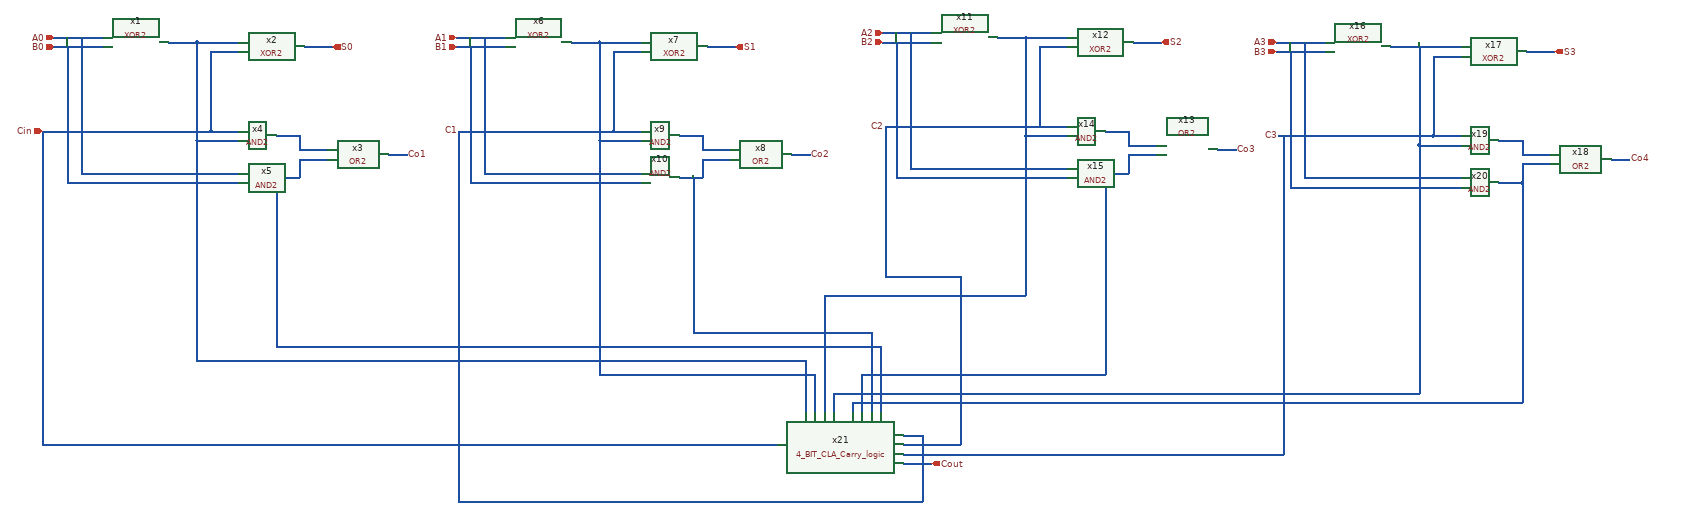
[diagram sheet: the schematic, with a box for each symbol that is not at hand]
v {xschem version=3.4.5 file_version=1.2
}
G {}
K {}
V {}
S {}
E {}
N 1850 -1470 1850 -1440 {
lab=#net1}
N 1850 -1440 1910 -1440 {
lab=#net1}
N 1850 -1420 1850 -1380 {
lab=#net2}
N 1850 -1420 1910 -1420 {
lab=#net2}
N 1660 -1650 1720 -1650 {
lab=Cin}
N 1660 -1650 1660 -1490 {
lab=Cin}
N 1660 -1490 1660 -1480 {
lab=Cin}
N 1660 -1480 1720 -1480 {
lab=Cin}
N 1630 -1460 1720 -1460 {
lab=#net3}
N 1630 -1670 1630 -1460 {
lab=#net3}
N 1630 -1670 1720 -1670 {
lab=#net3}
N 1570 -1670 1630 -1670 {
lab=#net3}
N 1800 -1470 1850 -1470 {
lab=#net1}
N 1800 -1380 1850 -1380 {
lab=#net2}
N 2040 -1430 2080 -1430 {
lab=Co1}
N 1860 -1660 1920 -1660 {
lab=S0}
N 1325 -1680 1430 -1680 {
lab=A0}
N 1325 -1660 1430 -1660 {
lab=B0}
N 1385 -1390 1720 -1390 {
lab=A0}
N 1385 -1680 1385 -1390 {
lab=A0}
N 1355 -1370 1720 -1370 {
lab=B0}
N 1355 -1660 1355 -1370 {
lab=B0}
N 1330 -1480 1660 -1480 {
lab=Cin}
N 2710 -1470 2710 -1440 {
lab=#net4}
N 2710 -1440 2770 -1440 {
lab=#net4}
N 2710 -1420 2710 -1380 {
lab=#net5}
N 2710 -1420 2770 -1420 {
lab=#net5}
N 2520 -1650 2580 -1650 {
lab=C1}
N 2520 -1650 2520 -1490 {
lab=C1}
N 2520 -1490 2520 -1480 {
lab=C1}
N 2520 -1480 2580 -1480 {
lab=C1}
N 2490 -1460 2580 -1460 {
lab=#net6}
N 2490 -1670 2490 -1460 {
lab=#net6}
N 2490 -1670 2580 -1670 {
lab=#net6}
N 2430 -1670 2490 -1670 {
lab=#net6}
N 2660 -1470 2710 -1470 {
lab=#net4}
N 2660 -1380 2710 -1380 {
lab=#net5}
N 2900 -1430 2940 -1430 {
lab=Co2}
N 2720 -1660 2780 -1660 {
lab=S1}
N 2185 -1680 2290 -1680 {
lab=A1}
N 2185 -1660 2290 -1660 {
lab=B1}
N 2245 -1390 2580 -1390 {
lab=A1}
N 2245 -1680 2245 -1390 {
lab=A1}
N 2215 -1370 2580 -1370 {
lab=B1}
N 2215 -1660 2215 -1370 {
lab=B1}
N 2190 -1480 2520 -1480 {
lab=C1}
N 3620 -1480 3620 -1450 {
lab=#net7}
N 3620 -1450 3680 -1450 {
lab=#net7}
N 3620 -1430 3620 -1390 {
lab=#net8}
N 3620 -1430 3680 -1430 {
lab=#net8}
N 3430 -1660 3490 -1660 {
lab=C2}
N 3430 -1660 3430 -1500 {
lab=C2}
N 3430 -1500 3430 -1490 {
lab=C2}
N 3430 -1490 3490 -1490 {
lab=C2}
N 3400 -1470 3490 -1470 {
lab=#net9}
N 3400 -1680 3400 -1470 {
lab=#net9}
N 3400 -1680 3490 -1680 {
lab=#net9}
N 3340 -1680 3400 -1680 {
lab=#net9}
N 3570 -1480 3620 -1480 {
lab=#net7}
N 3570 -1390 3620 -1390 {
lab=#net8}
N 3810 -1440 3850 -1440 {
lab=Co3}
N 3630 -1670 3690 -1670 {
lab=S2}
N 3095 -1690 3200 -1690 {
lab=A2}
N 3095 -1670 3200 -1670 {
lab=B2}
N 3155 -1400 3490 -1400 {
lab=A2}
N 3155 -1690 3155 -1400 {
lab=A2}
N 3125 -1380 3490 -1380 {
lab=B2}
N 3125 -1670 3125 -1380 {
lab=B2}
N 3100 -1490 3430 -1490 {
lab=C2}
N 4270 -1640 4330 -1640 {
lab=C3}
N 4270 -1640 4270 -1480 {
lab=C3}
N 4270 -1480 4270 -1470 {
lab=C3}
N 4270 -1470 4330 -1470 {
lab=C3}
N 4240 -1450 4330 -1450 {
lab=#net10}
N 4650 -1420 4690 -1420 {
lab=Co4}
N 4470 -1650 4530 -1650 {
lab=S3}
N 3935 -1670 4040 -1670 {
lab=A3}
N 3935 -1650 4040 -1650 {
lab=B3}
N 3995 -1380 4330 -1380 {
lab=A3}
N 3995 -1670 3995 -1380 {
lab=A3}
N 3965 -1360 4330 -1360 {
lab=B3}
N 3965 -1650 3965 -1360 {
lab=B3}
N 3940 -1470 4270 -1470 {
lab=C3}
N 1800 -1380 1800 -1020 {
lab=#net2}
N 1800 -1020 3090 -1020 {
lab=#net2}
N 3090 -1020 3090 -880 {
lab=#net2}
N 1630 -1460 1630 -990 {
lab=#net3}
N 1630 -990 2930 -990 {
lab=#net3}
N 2930 -990 2930 -880 {
lab=#net3}
N 2490 -1460 2490 -960 {
lab=#net6}
N 2490 -960 2940 -960 {
lab=#net6}
N 2940 -960 2950 -960 {
lab=#net6}
N 2950 -960 2950 -880 {
lab=#net6}
N 2690 -1380 2690 -1050 {
lab=#net5}
N 2690 -1050 3060 -1050 {
lab=#net5}
N 3060 -1050 3070 -1050 {
lab=#net5}
N 3070 -1050 3070 -880 {
lab=#net5}
N 2970 -1130 2970 -880 {
lab=#net9}
N 2970 -1130 3400 -1130 {
lab=#net9}
N 3400 -1470 3400 -1130 {
lab=#net9}
N 3570 -1390 3570 -960 {
lab=#net8}
N 3050 -960 3570 -960 {
lab=#net8}
N 3050 -960 3050 -880 {
lab=#net8}
N 4240 -1450 4240 -920 {
lab=#net10}
N 2990 -920 4240 -920 {
lab=#net10}
N 2990 -920 2990 -880 {
lab=#net10}
N 1300 -810 2870 -810 {
lab=Cin}
N 1300 -1480 1300 -810 {
lab=Cin}
N 1300 -1480 1330 -1480 {
lab=Cin}
N 2190 -1480 2190 -690 {
lab=C1}
N 2190 -690 3180 -690 {
lab=C1}
N 3180 -830 3180 -690 {
lab=C1}
N 3140 -830 3180 -830 {
lab=C1}
N 3100 -1490 3100 -1170 {
lab=C2}
N 3100 -1170 3260 -1170 {
lab=C2}
N 3260 -1170 3260 -810 {
lab=C2}
N 3140 -810 3260 -810 {
lab=C2}
N 3140 -790 3950 -790 {
lab=C3}
N 3950 -1470 3950 -790 {
lab=C3}
N 3140 -770 3200 -770 {
lab=Cout}
N 4460 -1430 4520 -1430 {
lab=#net11}
N 4460 -1460 4460 -1430 {
lab=#net11}
N 4410 -1460 4460 -1460 {
lab=#net11}
N 4180 -1660 4330 -1660 {
lab=#net10}
N 4240 -1660 4240 -1450 {
lab=#net10}
N 4460 -1410 4520 -1410 {
lab=#net12}
N 4460 -1410 4460 -1370 {
lab=#net12}
N 4410 -1370 4460 -1370 {
lab=#net12}
N 4460 -1370 4460 -900 {
lab=#net12}
N 3030 -900 4460 -900 {
lab=#net12}
N 3030 -900 3030 -880 {
lab=#net12}
C {XOR2.sym} 1490 -1670 0 0 {name=x1}
C {XOR2.sym} 1780 -1660 0 0 {name=x2}
C {OR2.sym} 1960 -1430 0 0 {name=x3}
C {AND2.sym} 1760 -1470 0 0 {name=x4}
C {AND2.sym} 1760 -1380 0 0 {name=x5}
C {devices/opin.sym} 1920 -1660 0 0 {name=p4 lab=S0}
C {devices/lab_pin.sym} 2080 -1430 2 0 {name=p5 lab=Co1}
C {devices/ipin.sym} 1325 -1680 0 0 {name=p1 sig_type=std_logic lab=A0}
C {devices/ipin.sym} 1325 -1660 0 0 {name=p2 sig_type=std_logic lab=B0}
C {devices/ipin.sym} 1300 -1480 0 0 {name=p3 sig_type=std_logic lab=Cin}
C {XOR2.sym} 2350 -1670 0 0 {name=x6}
C {XOR2.sym} 2640 -1660 0 0 {name=x7}
C {OR2.sym} 2820 -1430 0 0 {name=x8}
C {AND2.sym} 2620 -1470 0 0 {name=x9}
C {AND2.sym} 2620 -1380 0 0 {name=x10}
C {devices/opin.sym} 2780 -1660 0 0 {name=p8 lab=S1}
C {devices/ipin.sym} 2185 -1680 0 0 {name=p10 sig_type=std_logic lab=A1}
C {devices/ipin.sym} 2185 -1660 0 0 {name=p11 sig_type=std_logic lab=B1}
C {devices/lab_pin.sym} 2190 -1480 0 0 {name=p14 sig_type=std_logic lab=C1}
C {XOR2.sym} 3260 -1680 0 0 {name=x11}
C {XOR2.sym} 3550 -1670 0 0 {name=x12}
C {OR2.sym} 3730 -1440 0 0 {name=x13}
C {AND2.sym} 3530 -1480 0 0 {name=x14}
C {AND2.sym} 3530 -1390 0 0 {name=x15}
C {devices/opin.sym} 3690 -1670 0 0 {name=p17 lab=S2}
C {devices/ipin.sym} 3095 -1690 0 0 {name=p19 sig_type=std_logic lab=A2}
C {devices/ipin.sym} 3095 -1670 0 0 {name=p20 sig_type=std_logic lab=B2}
C {devices/lab_pin.sym} 3100 -1490 0 0 {name=p21 sig_type=std_logic lab=C2}
C {XOR2.sym} 4100 -1660 0 0 {name=x16}
C {XOR2.sym} 4390 -1650 0 0 {name=x17}
C {OR2.sym} 4570 -1420 0 0 {name=x18}
C {AND2.sym} 4370 -1460 0 0 {name=x19}
C {AND2.sym} 4370 -1370 0 0 {name=x20}
C {devices/opin.sym} 4530 -1650 0 0 {name=p24 lab=S3}
C {devices/ipin.sym} 3935 -1670 0 0 {name=p26 sig_type=std_logic lab=A3}
C {devices/ipin.sym} 3935 -1650 0 0 {name=p27 sig_type=std_logic lab=B3}
C {devices/lab_pin.sym} 3940 -1470 0 0 {name=p28 sig_type=std_logic lab=C3}
C {4_BIT_CLA_Carry_logic.sym} 2990 -780 0 0 {name=x21}
C {devices/opin.sym} 3200 -770 0 0 {name=p31 lab=Cout}
C {devices/lab_pin.sym} 2940 -1430 2 0 {name=p9 lab=Co2}
C {devices/lab_pin.sym} 3850 -1440 2 0 {name=p12 lab=Co3}
C {devices/lab_pin.sym} 4690 -1420 2 0 {name=p13 lab=Co4}
